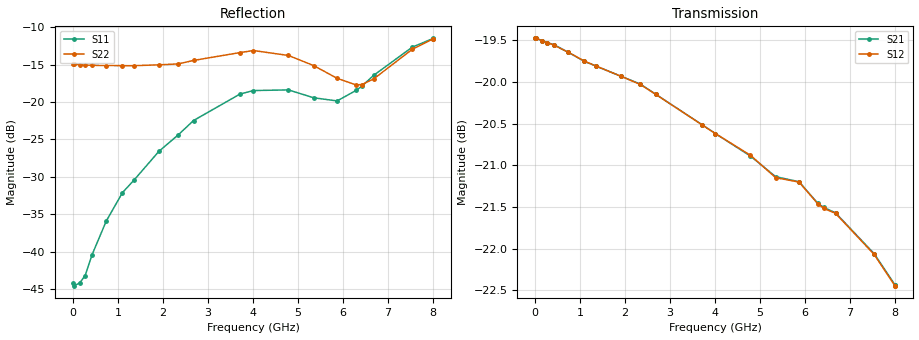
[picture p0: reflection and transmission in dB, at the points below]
! DEVICE ID: PE43712
! File Path: z:\PE43713\PE43713_CHAR_NOM_04292014\AMB\3p300\LS_ATT_18p25dB\PE43713_AMB_3p300V_3p000V_0p000V_LS_ATT_18p25dB_S2P_SN_10_A0139A.s2p
! Serial: 10
! Lot: A0139A
! Temp: 25C
! VDD: 3.300
! VSS: 0.000
! Control_Hi: 3.000
! Control_Lo: 0.000
! Attenuation Step: 18.25dB
! Port 1: RF1
! Port 2: RF2
! ThroughPath:1-2
! IDD: 0.0001464811
! ISS: -1.071e-007
#  Hz  S  RI  R  50
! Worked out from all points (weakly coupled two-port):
!   801 points, 10 MHz to 8.01 GHz, reference 50 ohm
!   highest |S21| = -19.48 dB at 10 MHz (marker M1); lowest = -22.4 dB at 8 GHz (marker M2)
!   lowest |S11| = -44.6 dB at 30 MHz (marker M3), VSWR 1.01, Z = 49.4 + j0.136 ohm
!   |S11| at or under -10 dB: start of sweep to end of sweep
!   |S22| runs from -17.7 to -11.6 dB; largest |S21 - S12| = 0.00039
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1e7  -0.00617 0.000554  0.1062 -0.000526  0.1062 -0.000514  -0.1798 0.00119
3e7  -0.00575 0.00138  0.1062 -0.00135  0.1062 -0.00136  -0.1792 0.00301
1.5e8  -0.00494 0.00371  0.1057 -0.00635  0.1057 -0.00635  -0.1777 0.0114
2.7e8  -0.00425 0.00544  0.105 -0.0112  0.105 -0.0112  -0.176 0.0183
4.2e8  -0.00392 0.00861  0.1039 -0.0171  0.1038 -0.0172  -0.174 0.0271
7.4e8  -0.0036 0.0156  0.1001 -0.0289  0.1001 -0.0289  -0.1688 0.0476
1.1e9  -0.00225 0.0247  0.0944 -0.0409  0.0944 -0.041  -0.1609 0.0694
1.35e9  0.000138 0.0299  0.0899 -0.0487  0.0899 -0.0487  -0.1542 0.0827
1.91e9  0.00874 0.046  0.0777 -0.0642  0.0777 -0.0642  -0.1336 0.1167
2.34e9  0.018 0.0576  0.0664 -0.0744  0.0663 -0.0744  -0.1143 0.1389
2.68e9  0.0268 0.0703  0.0566 -0.0804  0.0566 -0.0804  -0.0974 0.1629
3.71e9  0.0388 0.1061  0.0239 -0.0912  0.0238 -0.0912  -0.065 0.204
4.01e9  0.0399 0.1125  0.0144 -0.092  0.0144 -0.092  -0.0618 0.2122
4.79e9  0.0435 0.1124  -0.00914 -0.0898  -0.00917 -0.0899  -0.0425 0.2004
5.35e9  0.0559 0.091  -0.0243 -0.0843  -0.0242 -0.0842  -0.0232 0.1737
5.87e9  0.0767 0.0668  -0.038 -0.0784  -0.0379 -0.0784  0.0173 0.1431
6.29e9  0.1057 0.0557  -0.0477 -0.0698  -0.0476 -0.0698  0.0628 0.1141
6.42e9  0.1156 0.054  -0.05 -0.0676  -0.0498 -0.0676  0.0779 0.1052
6.68e9  0.1413 0.0522  -0.0552 -0.0626  -0.0551 -0.0626  0.109 0.0918
7.54e9  0.2243 0.0621  -0.0678 -0.0403  -0.0677 -0.0403  0.2071 0.0883
8e9  0.255 0.0757  -0.0697 -0.0292  -0.0695 -0.0294  0.2461 0.0952
8.01e9  0.2554 0.0764  -0.0697 -0.0291  -0.0696 -0.0292  0.2467 0.0951
